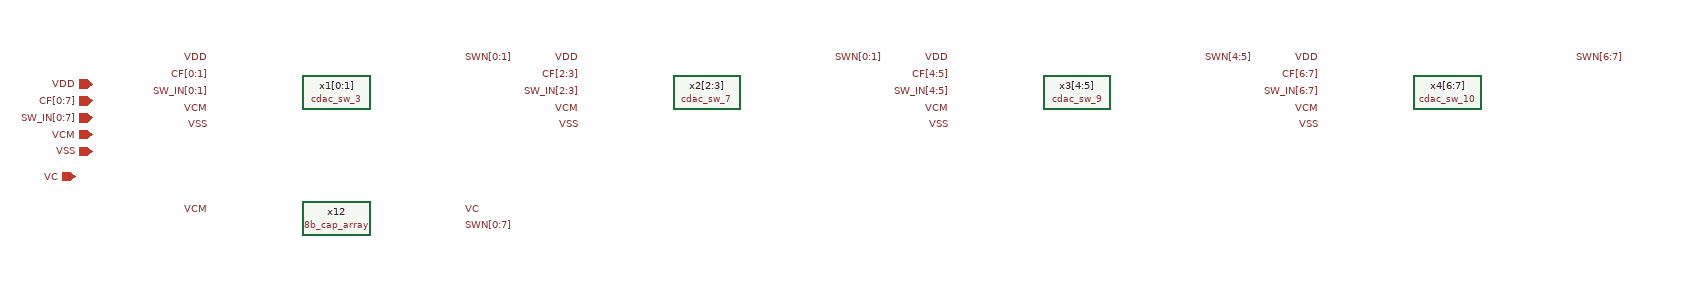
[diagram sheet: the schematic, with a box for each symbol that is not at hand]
v {xschem version=3.4.6 file_version=1.2}
G {}
K {}
V {}
S {}
E {}
C {devices/lab_wire.sym} 320 -430 0 0 {name=p9 sig_type=std_logic lab=VCM}
C {devices/lab_wire.sym} 620 -430 0 1 {name=p16 sig_type=std_logic lab=VC}
C {devices/ipin.sym} 180 -580 0 0 {name=p18 lab=VDD}
C {devices/ipin.sym} 180 -560 0 0 {name=p19 lab=CF[0:7]}
C {devices/ipin.sym} 180 -540 0 0 {name=p20 lab=SW_IN[0:7]}
C {devices/ipin.sym} 180 -520 0 0 {name=p22 lab=VCM}
C {devices/ipin.sym} 180 -500 0 0 {name=p23 lab=VSS}
C {devices/iopin.sym} 160 -470 0 0 {name=p24 lab=VC}
C {devices/lab_wire.sym} 620 -410 0 1 {name=p1 sig_type=std_logic lab=SWN[0:7]}
C {devices/lab_wire.sym} 320 -610 0 0 {name=p15 sig_type=std_logic lab=VDD}
C {devices/lab_wire.sym} 320 -530 0 0 {name=p17 sig_type=std_logic lab=VSS}
C {devices/lab_wire.sym} 620 -610 2 0 {name=p21 sig_type=std_logic lab=SWN[0:1]}
C {devices/lab_wire.sym} 320 -550 0 0 {name=p25 sig_type=std_logic lab=VCM}
C {devices/lab_wire.sym} 320 -590 0 0 {name=p26 sig_type=std_logic lab=CF[0:1]}
C {devices/lab_wire.sym} 320 -570 0 0 {name=p27 sig_type=std_logic lab=SW_IN[0:1]}
C {8b_cap_array.sym} 470 -420 0 0 {name=x12}
C {cdac_sw_3.sym} 470 -570 0 0 {name=x1[0:1]}
C {cdac_sw_7.sym} 910 -570 0 0 {name=x2[2:3]}
C {cdac_sw_9.sym} 1350 -570 0 0 {name=x3[4:5]}
C {cdac_sw_10.sym} 1790 -570 0 0 {name=x4[6:7]}
C {devices/lab_wire.sym} 760 -610 0 0 {name=p2 sig_type=std_logic lab=VDD}
C {devices/lab_wire.sym} 760 -530 0 0 {name=p3 sig_type=std_logic lab=VSS}
C {devices/lab_wire.sym} 1060 -610 2 0 {name=p4 sig_type=std_logic lab=SWN[0:1]}
C {devices/lab_wire.sym} 760 -550 0 0 {name=p5 sig_type=std_logic lab=VCM}
C {devices/lab_wire.sym} 760 -590 0 0 {name=p6 sig_type=std_logic lab=CF[2:3]}
C {devices/lab_wire.sym} 760 -570 0 0 {name=p7 sig_type=std_logic lab=SW_IN[2:3]}
C {devices/lab_wire.sym} 1200 -610 0 0 {name=p8 sig_type=std_logic lab=VDD}
C {devices/lab_wire.sym} 1200 -530 0 0 {name=p10 sig_type=std_logic lab=VSS}
C {devices/lab_wire.sym} 1500 -610 2 0 {name=p11 sig_type=std_logic lab=SWN[4:5]}
C {devices/lab_wire.sym} 1200 -550 0 0 {name=p12 sig_type=std_logic lab=VCM}
C {devices/lab_wire.sym} 1200 -590 0 0 {name=p13 sig_type=std_logic lab=CF[4:5]}
C {devices/lab_wire.sym} 1200 -570 0 0 {name=p14 sig_type=std_logic lab=SW_IN[4:5]}
C {devices/lab_wire.sym} 1640 -610 0 0 {name=p28 sig_type=std_logic lab=VDD}
C {devices/lab_wire.sym} 1640 -530 0 0 {name=p29 sig_type=std_logic lab=VSS}
C {devices/lab_wire.sym} 1940 -610 2 0 {name=p30 sig_type=std_logic lab=SWN[6:7]}
C {devices/lab_wire.sym} 1640 -550 0 0 {name=p31 sig_type=std_logic lab=VCM}
C {devices/lab_wire.sym} 1640 -590 0 0 {name=p32 sig_type=std_logic lab=CF[6:7]}
C {devices/lab_wire.sym} 1640 -570 0 0 {name=p33 sig_type=std_logic lab=SW_IN[6:7]}
